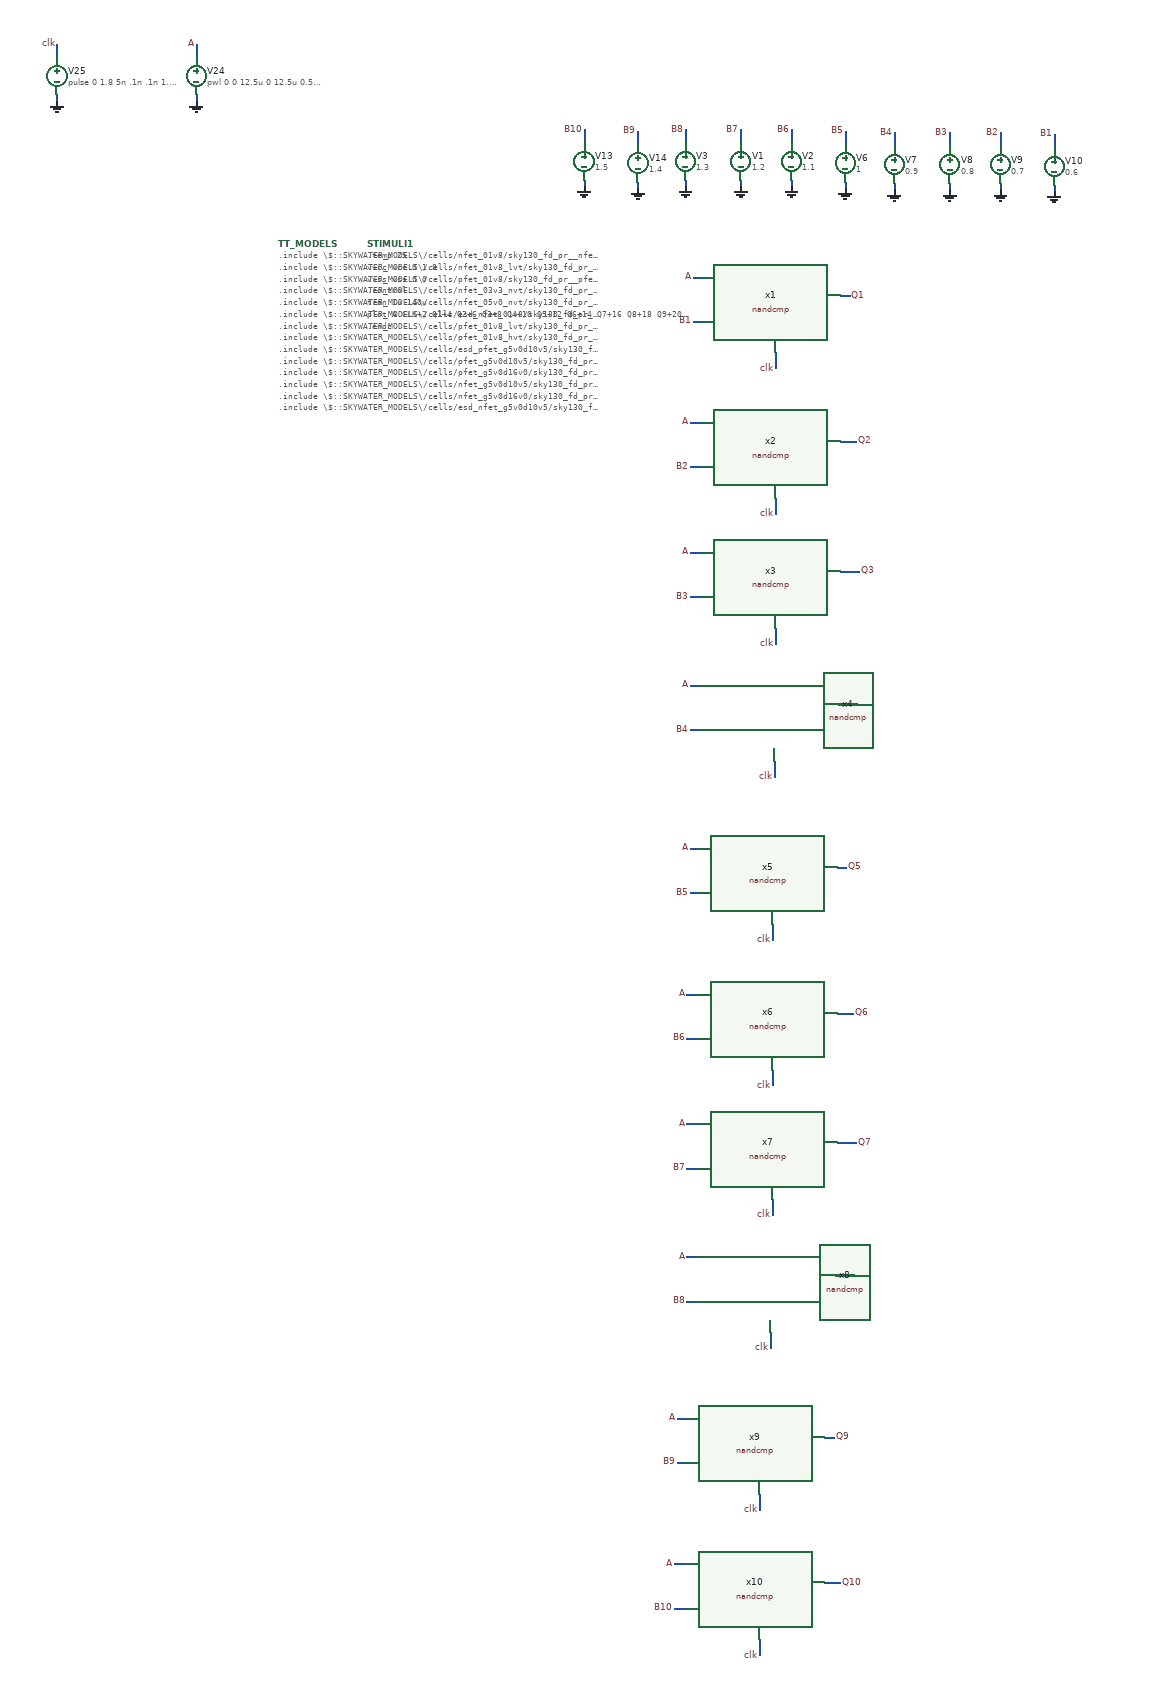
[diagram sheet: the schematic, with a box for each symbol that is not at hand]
v {xschem version=2.9.9 file_version=1.2 }
G {}
K {}
V {}
S {}
E {}
N -102.5 -12.5 -102.5 -7.5 { lab=clk}
N -102.5 -30 -102.5 -12.5 { lab=clk}
N -232.5 -152.5 -220 -152.5 { lab=A}
N -232.5 -82.5 -220 -82.5 { lab=B1}
N -102.5 -32.5 -102.5 -30 { lab=clk}
N 0 -122.5 15 -122.5 { lab=Q1}
N -245 -305 -245 -295 { lab=GND}
N -245 -385 -245 -365 { lab=B8}
N -102.5 217.5 -102.5 222.5 { lab=clk}
N -105 632.5 -105 637.5 { lab=clk}
N -105 615 -105 632.5 { lab=clk}
N -105 612.5 -105 615 { lab=clk}
N -157.5 -305 -157.5 -295 { lab=GND}
N -157.5 -385 -157.5 -365 { lab=B7}
N -77.5 -305 -77.5 -295 { lab=GND}
N -77.5 -385 -77.5 -365 { lab=B6}
N 7.5 -302.5 7.5 -292.5 { lab=GND}
N 7.5 -382.5 7.5 -362.5 { lab=B5}
N -237.5 492.5 -222.5 492.5 { lab=A}
N -237.5 562.5 -222.5 562.5 { lab=B4}
N -2.5 522.5 27.5 522.5 { lab=Q4}
N -237.5 77.5 -220 77.5 { lab=A}
N -102.5 402.5 -102.5 427.5 { lab=clk}
N -237.5 282.5 -232.5 282.5 { lab=A}
N -232.5 282.5 -220 282.5 { lab=A}
N -237.5 352.5 -220 352.5 { lab=B3}
N -237.5 147.5 -220 147.5 { lab=B2}
N -102.5 197.5 -102.5 217.5 { lab=clk}
N 0 107.5 25 107.5 { lab=Q2}
N 0 312.5 30 312.5 { lab=Q3}
N -107.5 890 -107.5 895 { lab=clk}
N -107.5 872.5 -107.5 890 { lab=clk}
N -237.5 750 -225 750 { lab=A}
N -237.5 820 -225 820 { lab=B5}
N -107.5 870 -107.5 872.5 { lab=clk}
N -5 780 10 780 { lab=Q5}
N -107.5 1120 -107.5 1125 { lab=clk}
N -110 1535 -110 1540 { lab=clk}
N -110 1517.5 -110 1535 { lab=clk}
N -110 1515 -110 1517.5 { lab=clk}
N -242.5 1395 -227.5 1395 { lab=A}
N -242.5 1465 -227.5 1465 { lab=B8}
N -7.5 1425 22.5 1425 { lab=Q8}
N -242.5 980 -225 980 { lab=A}
N -107.5 1305 -107.5 1330 { lab=clk}
N -242.5 1185 -237.5 1185 { lab=A}
N -237.5 1185 -225 1185 { lab=A}
N -242.5 1255 -225 1255 { lab=B7}
N -242.5 1050 -225 1050 { lab=B6}
N -107.5 1100 -107.5 1120 { lab=clk}
N -5 1010 20 1010 { lab=Q6}
N -5 1215 25 1215 { lab=Q7}
N 85 -300 85 -290 { lab=GND}
N 85 -380 85 -360 { lab=B4}
N 172.5 -300 172.5 -290 { lab=GND}
N 172.5 -380 172.5 -360 { lab=B3}
N 252.5 -300 252.5 -290 { lab=GND}
N 252.5 -380 252.5 -360 { lab=B2}
N 337.5 -297.5 337.5 -287.5 { lab=GND}
N 337.5 -377.5 337.5 -357.5 { lab=B1}
N -405 -305 -405 -295 { lab=GND}
N -405 -385 -405 -365 { lab=B10}
N -320 -302.5 -320 -292.5 { lab=GND}
N -320 -382.5 -320 -362.5 { lab=B9}
N -127.5 1790 -127.5 1795 { lab=clk}
N -127.5 1772.5 -127.5 1790 { lab=clk}
N -257.5 1650 -245 1650 { lab=A}
N -257.5 1720 -245 1720 { lab=B9}
N -127.5 1770 -127.5 1772.5 { lab=clk}
N -25 1680 -10 1680 { lab=Q9}
N -127.5 2020 -127.5 2025 { lab=clk}
N -262.5 1880 -245 1880 { lab=A}
N -262.5 1950 -245 1950 { lab=B10}
N -127.5 2000 -127.5 2020 { lab=clk}
N -25 1910 0 1910 { lab=Q10}
N -1017.5 -440 -1017.5 -430 { lab=GND}
N -1237.5 -440 -1237.5 -430 { lab=GND}
N -1237.5 -520 -1237.5 -500 { lab=clk}
N -1017.5 -520 -1017.5 -500 { lab=A}
C {devices/lab_pin.sym} -232.5 -152.5 0 0 {name=l1 sig_type=std_logic lab=A}
C {devices/lab_pin.sym} -232.5 -82.5 0 0 {name=l2 sig_type=std_logic lab=B1}
C {devices/lab_pin.sym} -102.5 -7.5 0 0 {name=l3 sig_type=std_logic lab=clk}
C {devices/lab_pin.sym} 15 -122.5 2 0 {name=l4 sig_type=std_logic lab=Q1}
C {devices/vsource.sym} -245 -335 0 0 {name=V3 value=1.3}
C {devices/gnd.sym} -245 -295 0 0 {name=l13 lab=GND}
C {devices/lab_pin.sym} -245 -385 0 0 {name=l14 sig_type=std_logic lab=B8
}
C {devices/code.sym} -747.5 -205 0 0 {name=STIMULI1 
only_toplevel=true
place=end
value="
.temp 25
vvcc vcc 0 1.8
vvss vss 0 0
.control
tran 1u 140u
plot A CLK+2 Q1+4 Q2+6 Q3+8 Q4+10 Q5+12 Q6+14 Q7+16 Q8+18 Q9+20 Q10+22 
.endc
"}
C {devices/lab_pin.sym} -102.5 222.5 0 0 {name=l5 sig_type=std_logic lab=clk}
C {devices/lab_pin.sym} -102.5 427.5 0 0 {name=l6 sig_type=std_logic lab=clk}
C {devices/lab_pin.sym} -105 637.5 0 0 {name=l7 sig_type=std_logic lab=clk}
C {devices/vsource.sym} -157.5 -335 0 0 {name=V1 value=1.2}
C {devices/gnd.sym} -157.5 -295 0 0 {name=l8 lab=GND}
C {devices/lab_pin.sym} -157.5 -385 0 0 {name=l9 sig_type=std_logic lab=B7
}
C {devices/vsource.sym} -77.5 -335 0 0 {name=V2 value=1.1}
C {devices/gnd.sym} -77.5 -295 0 0 {name=l10 lab=GND}
C {devices/lab_pin.sym} -77.5 -385 0 0 {name=l17 sig_type=std_logic lab=B6
}
C {devices/vsource.sym} 7.5 -332.5 0 0 {name=V6 value=1}
C {devices/gnd.sym} 7.5 -292.5 0 0 {name=l18 lab=GND}
C {devices/lab_pin.sym} 7.5 -382.5 0 0 {name=l19 sig_type=std_logic lab=B5
}
C {devices/lab_pin.sym} -237.5 77.5 0 0 {name=l20 sig_type=std_logic lab=A}
C {devices/lab_pin.sym} -237.5 147.5 0 0 {name=l21 sig_type=std_logic lab=B2}
C {devices/lab_pin.sym} -237.5 282.5 0 0 {name=l22 sig_type=std_logic lab=A}
C {devices/lab_pin.sym} -237.5 352.5 0 0 {name=l23 sig_type=std_logic lab=B3}
C {devices/lab_pin.sym} -237.5 492.5 0 0 {name=l24 sig_type=std_logic lab=A}
C {devices/lab_pin.sym} -237.5 562.5 0 0 {name=l25 sig_type=std_logic lab=B4}
C {devices/lab_pin.sym} 25 107.5 2 0 {name=l26 sig_type=std_logic lab=Q2}
C {devices/lab_pin.sym} 30 312.5 2 0 {name=l27 sig_type=std_logic lab=Q3}
C {devices/lab_pin.sym} 25 522.5 2 0 {name=l28 sig_type=std_logic lab=Q4}
C {devices/lab_pin.sym} -237.5 750 0 0 {name=l29 sig_type=std_logic lab=A}
C {devices/lab_pin.sym} -237.5 820 0 0 {name=l30 sig_type=std_logic lab=B5}
C {devices/lab_pin.sym} -107.5 895 0 0 {name=l31 sig_type=std_logic lab=clk}
C {devices/lab_pin.sym} 10 780 2 0 {name=l32 sig_type=std_logic lab=Q5}
C {devices/lab_pin.sym} -107.5 1125 0 0 {name=l33 sig_type=std_logic lab=clk}
C {devices/lab_pin.sym} -107.5 1330 0 0 {name=l34 sig_type=std_logic lab=clk}
C {devices/lab_pin.sym} -110 1540 0 0 {name=l35 sig_type=std_logic lab=clk}
C {devices/lab_pin.sym} -242.5 980 0 0 {name=l36 sig_type=std_logic lab=A}
C {devices/lab_pin.sym} -242.5 1050 0 0 {name=l37 sig_type=std_logic lab=B6}
C {devices/lab_pin.sym} -242.5 1185 0 0 {name=l38 sig_type=std_logic lab=A}
C {devices/lab_pin.sym} -242.5 1255 0 0 {name=l39 sig_type=std_logic lab=B7}
C {devices/lab_pin.sym} -242.5 1395 0 0 {name=l40 sig_type=std_logic lab=A}
C {devices/lab_pin.sym} -242.5 1465 0 0 {name=l41 sig_type=std_logic lab=B8}
C {devices/lab_pin.sym} 20 1010 2 0 {name=l42 sig_type=std_logic lab=Q6}
C {devices/lab_pin.sym} 25 1215 2 0 {name=l43 sig_type=std_logic lab=Q7}
C {devices/lab_pin.sym} 20 1425 2 0 {name=l44 sig_type=std_logic lab=Q8}
C {devices/vsource.sym} 85 -330 0 0 {name=V7 value=0.9}
C {devices/gnd.sym} 85 -290 0 0 {name=l45 lab=GND}
C {devices/lab_pin.sym} 85 -380 0 0 {name=l46 sig_type=std_logic lab=B4
}
C {devices/vsource.sym} 172.5 -330 0 0 {name=V8 value=0.8}
C {devices/gnd.sym} 172.5 -290 0 0 {name=l47 lab=GND}
C {devices/lab_pin.sym} 172.5 -380 0 0 {name=l48 sig_type=std_logic lab=B3
}
C {devices/vsource.sym} 252.5 -330 0 0 {name=V9 value=0.7}
C {devices/gnd.sym} 252.5 -290 0 0 {name=l49 lab=GND}
C {devices/lab_pin.sym} 252.5 -380 0 0 {name=l50 sig_type=std_logic lab=B2
}
C {devices/vsource.sym} 337.5 -327.5 0 0 {name=V10 value=0.6}
C {devices/gnd.sym} 337.5 -287.5 0 0 {name=l51 lab=GND}
C {devices/lab_pin.sym} 337.5 -377.5 0 0 {name=l52 sig_type=std_logic lab=B1
}
C {nandcmp.sym} -110 -77.5 0 0 {name=x1}
C {nandcmp.sym} -110 152.5 0 0 {name=x2}
C {nandcmp.sym} -110 357.5 0 0 {name=x3}
C {nandcmp.sym} -112.5 567.5 0 0 {name=x4}
C {nandcmp.sym} -115 825 0 0 {name=x5}
C {nandcmp.sym} -115 1055 0 0 {name=x6}
C {nandcmp.sym} -115 1260 0 0 {name=x7}
C {nandcmp.sym} -117.5 1470 0 0 {name=x8}
C {devices/code.sym} -887.5 -205 0 0 {name=TT_MODELS
only_toplevel=true
format="tcleval( @value )"
value="
.include \\\\$::SKYWATER_MODELS\\\\/cells/nfet_01v8/sky130_fd_pr__nfet_01v8__tt.corner.spice
.include \\\\$::SKYWATER_MODELS\\\\/cells/nfet_01v8_lvt/sky130_fd_pr__nfet_01v8_lvt__tt.corner.spice
.include \\\\$::SKYWATER_MODELS\\\\/cells/pfet_01v8/sky130_fd_pr__pfet_01v8__tt.corner.spice
.include \\\\$::SKYWATER_MODELS\\\\/cells/nfet_03v3_nvt/sky130_fd_pr__nfet_03v3_nvt__tt.corner.spice
.include \\\\$::SKYWATER_MODELS\\\\/cells/nfet_05v0_nvt/sky130_fd_pr__nfet_05v0_nvt__tt.corner.spice
.include \\\\$::SKYWATER_MODELS\\\\/cells/esd_nfet_01v8/sky130_fd_pr__esd_nfet_01v8__tt.corner.spice
.include \\\\$::SKYWATER_MODELS\\\\/cells/pfet_01v8_lvt/sky130_fd_pr__pfet_01v8_lvt__tt.corner.spice
.include \\\\$::SKYWATER_MODELS\\\\/cells/pfet_01v8_hvt/sky130_fd_pr__pfet_01v8_hvt__tt.corner.spice
.include \\\\$::SKYWATER_MODELS\\\\/cells/esd_pfet_g5v0d10v5/sky130_fd_pr__esd_pfet_g5v0d10v5__tt.corner.spice
.include \\\\$::SKYWATER_MODELS\\\\/cells/pfet_g5v0d10v5/sky130_fd_pr__pfet_g5v0d10v5__tt.corner.spice
.include \\\\$::SKYWATER_MODELS\\\\/cells/pfet_g5v0d16v0/sky130_fd_pr__pfet_g5v0d16v0__tt.corner.spice
.include \\\\$::SKYWATER_MODELS\\\\/cells/nfet_g5v0d10v5/sky130_fd_pr__nfet_g5v0d10v5__tt.corner.spice
.include \\\\$::SKYWATER_MODELS\\\\/cells/nfet_g5v0d16v0/sky130_fd_pr__nfet_g5v0d16v0__tt_discrete.corner.spice
.include \\\\$::SKYWATER_MODELS\\\\/cells/esd_nfet_g5v0d10v5/sky130_fd_pr__esd_nfet_g5v0d10v5__tt.corner.spice
.include \\\\$::SKYWATER_MODELS\\\\/models/corners/tt/nonfet.spice
* Mismatch parameters
.include \\\\$::SKYWATER_MODELS\\\\/cells/nfet_01v8/sky130_fd_pr__nfet_01v8__mismatch.corner.spice
.include \\\\$::SKYWATER_MODELS\\\\/cells/pfet_01v8/sky130_fd_pr__pfet_01v8__mismatch.corner.spice
.include \\\\$::SKYWATER_MODELS\\\\/cells/nfet_01v8_lvt/sky130_fd_pr__nfet_01v8_lvt__mismatch.corner.spice
.include \\\\$::SKYWATER_MODELS\\\\/cells/pfet_01v8_lvt/sky130_fd_pr__pfet_01v8_lvt__mismatch.corner.spice
.include \\\\$::SKYWATER_MODELS\\\\/cells/pfet_01v8_hvt/sky130_fd_pr__pfet_01v8_hvt__mismatch.corner.spice
.include \\\\$::SKYWATER_MODELS\\\\/cells/nfet_g5v0d10v5/sky130_fd_pr__nfet_g5v0d10v5__mismatch.corner.spice
.include \\\\$::SKYWATER_MODELS\\\\/cells/pfet_g5v0d10v5/sky130_fd_pr__pfet_g5v0d10v5__mismatch.corner.spice
.include \\\\$::SKYWATER_MODELS\\\\/cells/nfet_05v0_nvt/sky130_fd_pr__nfet_05v0_nvt__mismatch.corner.spice
.include \\\\$::SKYWATER_MODELS\\\\/cells/nfet_03v3_nvt/sky130_fd_pr__nfet_03v3_nvt__mismatch.corner.spice
* Resistor\\\\$::SKYWATER_MODELS\\\\/Capacitor
.include \\\\$::SKYWATER_MODELS\\\\/models/r+c/res_typical__cap_typical.spice
.include \\\\$::SKYWATER_MODELS\\\\/models/r+c/res_typical__cap_typical__lin.spice
* Special cells
.include \\\\$::SKYWATER_MODELS\\\\/models/corners/tt/specialized_cells.spice
* All models
.include \\\\$::SKYWATER_MODELS\\\\/models/all.spice
* Corner
.include \\\\$::SKYWATER_MODELS\\\\/models/corners/tt/rf.spice
.include ~/skywater-pdk/libraries/sky130_fd_sc_hd/latest/cells/nand3/sky130_fd_sc_hd__nand3_1.spice
.include ~/skywater-pdk/libraries/sky130_fd_sc_hd/latest/cells/nand2/sky130_fd_sc_hd__nand2_1.spice
.include ~/skywater-pdk/libraries/sky130_fd_sc_hd/latest/cells/nor3/sky130_fd_sc_hd__nor3_1.spice
.include ~/skywater-pdk/libraries/sky130_fd_sc_hd/latest/cells/dfrtp/sky130_fd_sc_hd__dfrtp_1.spice
.include ~/skywater-pdk/libraries/sky130_fd_sc_hd/latest/cells/nor2/sky130_fd_sc_hd__nor2_1.spice
.include ~/skywater-pdk/libraries/sky130_fd_sc_hd/latest/cells/dlrbn/sky130_fd_sc_hd__dlrbn_1.spice
.include ~/skywater-pdk/libraries/sky130_fd_sc_hd/latest/cells/a31o/sky130_fd_sc_hd__a31o_2.spice
.include ~/skywater-pdk/libraries/sky130_fd_sc_hd/latest/cells/inv/sky130_fd_sc_hd__inv_1.spice
"}
C {devices/vsource.sym} -405 -335 0 0 {name=V13 value=1.5}
C {devices/gnd.sym} -405 -295 0 0 {name=l57 lab=GND}
C {devices/lab_pin.sym} -405 -385 0 0 {name=l58 sig_type=std_logic lab=B10
}
C {devices/vsource.sym} -320 -332.5 0 0 {name=V14 value=1.4}
C {devices/gnd.sym} -320 -292.5 0 0 {name=l59 lab=GND}
C {devices/lab_pin.sym} -320 -382.5 0 0 {name=l60 sig_type=std_logic lab=B9
}
C {devices/lab_pin.sym} -257.5 1650 0 0 {name=l61 sig_type=std_logic lab=A}
C {devices/lab_pin.sym} -257.5 1720 0 0 {name=l62 sig_type=std_logic lab=B9}
C {devices/lab_pin.sym} -127.5 1795 0 0 {name=l63 sig_type=std_logic lab=clk}
C {devices/lab_pin.sym} -10 1680 2 0 {name=l64 sig_type=std_logic lab=Q9}
C {devices/lab_pin.sym} -127.5 2025 0 0 {name=l65 sig_type=std_logic lab=clk}
C {devices/lab_pin.sym} -262.5 1880 0 0 {name=l68 sig_type=std_logic lab=A}
C {devices/lab_pin.sym} -262.5 1950 0 0 {name=l69 sig_type=std_logic lab=B10}
C {devices/lab_pin.sym} 0 1910 2 0 {name=l74 sig_type=std_logic lab=Q10}
C {nandcmp.sym} -135 1725 0 0 {name=x9}
C {nandcmp.sym} -135 1955 0 0 {name=x10}
C {devices/vsource.sym} -1017.5 -470 0 0 {name=V24 value="pwl 0 0 12.5u 0 12.5u 0.55 22.5u 0.55 22.5u 0.65 32.5u 0.65 32.5u 0.75 42.5u 0.75 42.5u 0.85 52.5u 0.85 52.5u 0.95 62.5u .95 62.5u 1.05 72.5u 1.05 72.5u 1.15 82.5u 1.15 82.5u 1.25 92.5u 1.25 92.5u 1.35 102.5u 1.35 102.5u 1.45 112.5u 1.45 112.5u 1.55 122.5u 1.55 122.5u 1.65 132.5u 1.65"}
C {devices/gnd.sym} -1237.5 -430 0 0 {name=l127 lab=GND}
C {devices/gnd.sym} -1017.5 -430 0 0 {name=l128 lab=GND}
C {devices/lab_pin.sym} -1017.5 -520 0 0 {name=l129 sig_type=std_logic lab=A
}
C {devices/lab_pin.sym} -1237.5 -520 0 0 {name=l130 sig_type=std_logic lab=clk}
C {devices/vsource.sym} -1237.5 -470 0 0 {name=V25 value="pulse 0 1.8 5n .1n .1n 1.225u 2.5u"}
